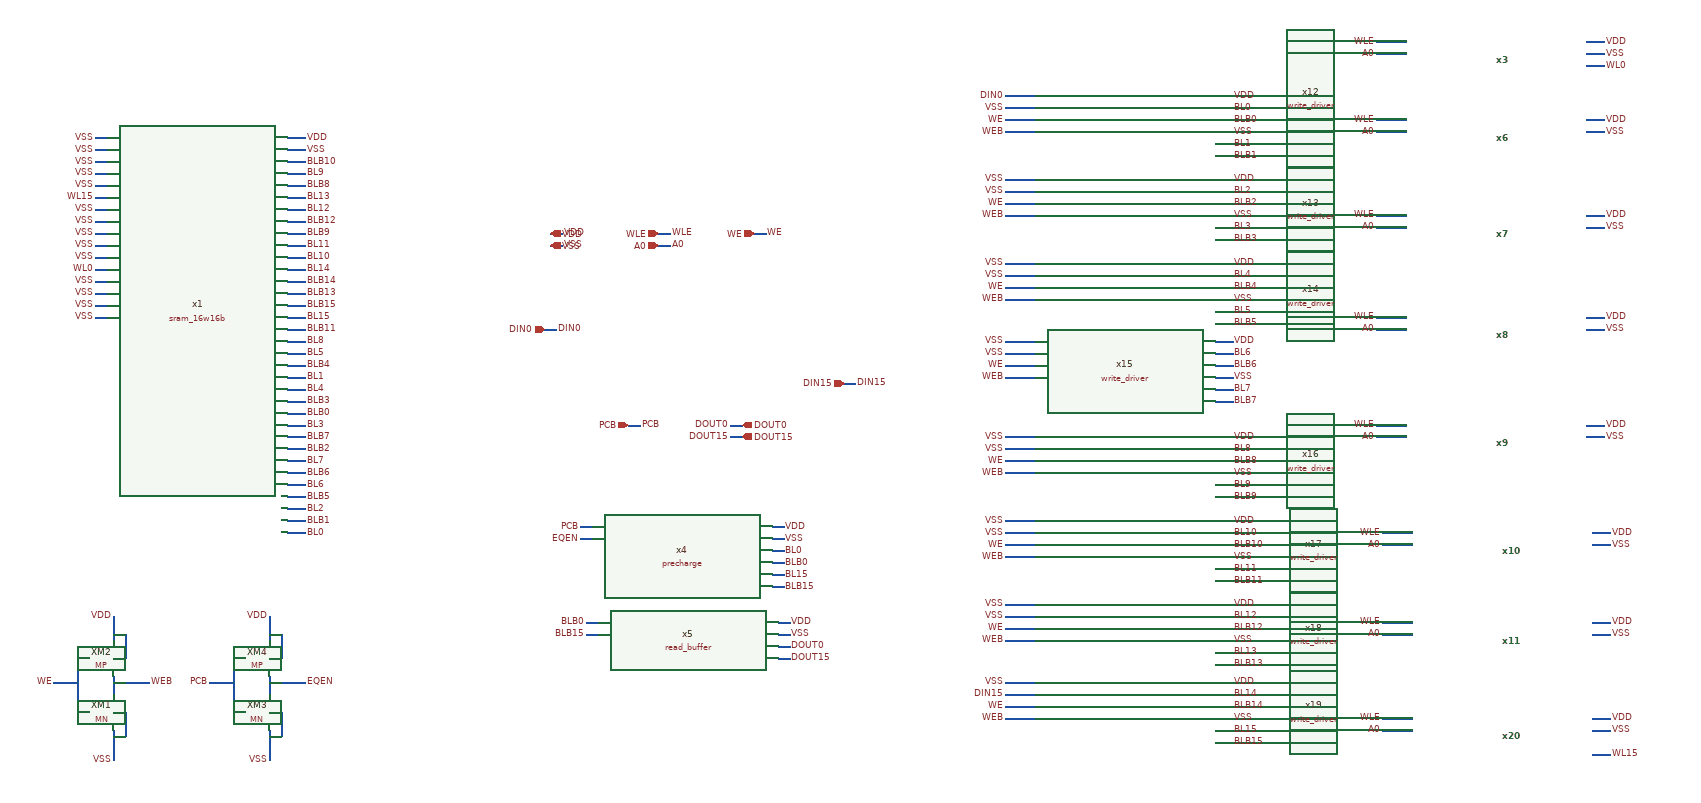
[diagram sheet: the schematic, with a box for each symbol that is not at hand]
v {xschem version=3.4.8RC file_version=1.3}
G {}
K {}
V {}
S {}
F {}
E {}
N 210 -880 230 -880 {lab=WL0}
N 210 -800 230 -800 {lab=VSS}
N 1020 -450 1040 -450 {lab=PCB}
N 1020 -430 1040 -430 {lab=EQEN}
N 1030 -290 1050 -290 {lab=BLB0}
N 1030 -270 1050 -270 {lab=BLB15}
N 1340 -450 1360 -450 {lab=VDD}
N 1340 -430 1360 -430 {lab=VSS}
N 1340 -410 1360 -410 {lab=BL0}
N 1340 -390 1360 -390 {lab=BLB0}
N 1340 -370 1360 -370 {lab=BL15}
N 1340 -350 1360 -350 {lab=BLB15}
N 1350 -290 1370 -290 {lab=VDD}
N 1350 -270 1370 -270 {lab=VSS}
N 1350 -250 1370 -250 {lab=DOUT0}
N 1350 -230 1370 -230 {lab=DOUT15}
N 970 -940 990 -940 {lab=VDD}
N 970 -920 990 -920 {lab=VSS}
N 1150 -940 1170 -940 {lab=WLE}
N 1150 -920 1170 -920 {lab=A0}
N 1310 -940 1330 -940 {lab=WE}
N 960 -780 980 -780 {lab=DIN0}
N 1100 -620 1120 -620 {lab=PCB}
N 1270 -620 1290 -620 {lab=DOUT0}
N 1270 -600 1290 -600 {lab=DOUT15}
N 240 -200 240 -170 {lab=WEB}
N 240 -110 240 -60 {lab=VSS}
N 240 -140 260 -140 {lab=VSS}
N 260 -140 260 -100 {lab=VSS}
N 240 -100 260 -100 {lab=VSS}
N 240 -300 240 -260 {lab=VDD}
N 180 -230 200 -230 {lab=WE}
N 180 -230 180 -140 {lab=WE}
N 180 -140 200 -140 {lab=WE}
N 240 -190 300 -190 {lab=WEB}
N 140 -190 180 -190 {lab=WE}
N 240 -230 260 -230 {lab=VDD}
N 260 -270 260 -230 {lab=VDD}
N 240 -270 260 -270 {lab=VDD}
N 500 -200 500 -170 {lab=EQEN}
N 500 -110 500 -60 {lab=VSS}
N 500 -140 520 -140 {lab=VSS}
N 520 -140 520 -100 {lab=VSS}
N 500 -100 520 -100 {lab=VSS}
N 500 -300 500 -260 {lab=VDD}
N 440 -230 460 -230 {lab=PCB}
N 440 -230 440 -140 {lab=PCB}
N 440 -140 460 -140 {lab=PCB}
N 500 -190 560 -190 {lab=EQEN}
N 400 -190 440 -190 {lab=PCB}
N 500 -230 520 -230 {lab=VDD}
N 520 -270 520 -230 {lab=VDD}
N 500 -270 520 -270 {lab=VDD}
N 530 -1080 560 -1080 {lab=VSS}
N 530 -1100 560 -1100 {lab=VDD}
N 530 -820 560 -820 {lab=BLB15}
N 530 -780 560 -780 {lab=BLB11}
N 530 -1020 560 -1020 {lab=BLB8}
N 530 -760 560 -760 {lab=BL8}
N 530 -960 560 -960 {lab=BLB12}
N 530 -1040 560 -1040 {lab=BL9}
N 530 -1060 560 -1060 {lab=BLB10}
N 530 -920 560 -920 {lab=BL11}
N 530 -900 560 -900 {lab=BL10}
N 530 -880 560 -880 {lab=BL14}
N 530 -840 560 -840 {lab=BLB13}
N 530 -980 560 -980 {lab=BL12}
N 530 -940 560 -940 {lab=BLB9}
N 530 -860 560 -860 {lab=BLB14}
N 530 -800 560 -800 {lab=BL15}
N 530 -1000 560 -1000 {lab=BL13}
N 530 -680 560 -680 {lab=BL4}
N 530 -640 560 -640 {lab=BLB0}
N 530 -620 560 -620 {lab=BL3}
N 530 -740 560 -740 {lab=BL5}
N 530 -700 560 -700 {lab=BL1}
N 530 -720 560 -720 {lab=BLB4}
N 530 -660 560 -660 {lab=BLB3}
N 530 -600 560 -600 {lab=BLB7}
N 530 -520 560 -520 {lab=BL6}
N 530 -480 560 -480 {lab=BL2}
N 530 -460 560 -460 {lab=BLB1}
N 530 -580 560 -580 {lab=BLB2}
N 530 -540 560 -540 {lab=BLB6}
N 530 -560 560 -560 {lab=BL7}
N 530 -500 560 -500 {lab=BLB5}
N 530 -440 560 -440 {lab=BL0}
N 2080 -1170 2110 -1170 {lab=VDD}
N 2080 -1110 2110 -1110 {lab=VSS}
N 1730 -1130 1780 -1130 {lab=WE}
N 1730 -1110 1780 -1110 {lab=WEB}
N 2080 -1150 2110 -1150 {lab=BL0}
N 2080 -1130 2110 -1130 {lab=BLB0}
N 2080 -1090 2110 -1090 {lab=BL1}
N 2080 -1070 2110 -1070 {lab=BLB1}
N 1730 -1170 1780 -1170 {lab=DIN0}
N 1730 -1150 1780 -1150 {lab=DIN1}
N 2080 -1030 2110 -1030 {lab=VDD}
N 2080 -970 2110 -970 {lab=VSS}
N 1730 -990 1780 -990 {lab=WE}
N 1730 -970 1780 -970 {lab=WEB}
N 2080 -1010 2110 -1010 {lab=BL2}
N 2080 -990 2110 -990 {lab=BLB2}
N 2080 -950 2110 -950 {lab=BL3}
N 2080 -930 2110 -930 {lab=BLB3}
N 1730 -1030 1780 -1030 {lab=DIN2}
N 1730 -1010 1780 -1010 {lab=DIN3}
N 2080 -890 2110 -890 {lab=VDD}
N 2080 -830 2110 -830 {lab=VSS}
N 1730 -850 1780 -850 {lab=WE}
N 1730 -830 1780 -830 {lab=WEB}
N 2080 -870 2110 -870 {lab=BL4}
N 2080 -850 2110 -850 {lab=BLB4}
N 2080 -810 2110 -810 {lab=BL5}
N 2080 -790 2110 -790 {lab=BLB5}
N 1730 -890 1780 -890 {lab=DIN4}
N 1730 -870 1780 -870 {lab=DIN5}
N 2080 -760 2110 -760 {lab=VDD}
N 2080 -700 2110 -700 {lab=VSS}
N 1730 -720 1780 -720 {lab=WE}
N 1730 -700 1780 -700 {lab=WEB}
N 2080 -740 2110 -740 {lab=BL6}
N 2080 -720 2110 -720 {lab=BLB6}
N 2080 -680 2110 -680 {lab=BL7}
N 2080 -660 2110 -660 {lab=BLB7}
N 1730 -760 1780 -760 {lab=DIN6}
N 1730 -740 1780 -740 {lab=DIN7}
N 2080 -600 2110 -600 {lab=VDD}
N 2080 -540 2110 -540 {lab=VSS}
N 1730 -560 1780 -560 {lab=WE}
N 1730 -540 1780 -540 {lab=WEB}
N 2080 -580 2110 -580 {lab=BL8}
N 2080 -560 2110 -560 {lab=BLB8}
N 2080 -520 2110 -520 {lab=BL9}
N 2080 -500 2110 -500 {lab=BLB9}
N 1730 -600 1780 -600 {lab=DIN8}
N 1730 -580 1780 -580 {lab=DIN9}
N 2080 -460 2110 -460 {lab=VDD}
N 2080 -400 2110 -400 {lab=VSS}
N 1730 -420 1780 -420 {lab=WE}
N 1730 -400 1780 -400 {lab=WEB}
N 2080 -440 2110 -440 {lab=BL10}
N 2080 -420 2110 -420 {lab=BLB10}
N 2080 -380 2110 -380 {lab=BL11}
N 2080 -360 2110 -360 {lab=BLB11}
N 1730 -460 1780 -460 {lab=DIN10}
N 1730 -440 1780 -440 {lab=DIN11}
N 2080 -320 2110 -320 {lab=VDD}
N 2080 -260 2110 -260 {lab=VSS}
N 1730 -280 1780 -280 {lab=WE}
N 1730 -260 1780 -260 {lab=WEB}
N 2080 -300 2110 -300 {lab=BL12}
N 2080 -280 2110 -280 {lab=BLB12}
N 2080 -240 2110 -240 {lab=BL13}
N 2080 -220 2110 -220 {lab=BLB13}
N 1730 -320 1780 -320 {lab=DIN12}
N 1730 -300 1780 -300 {lab=DIN13}
N 2080 -190 2110 -190 {lab=VDD}
N 2080 -130 2110 -130 {lab=VSS}
N 1730 -150 1780 -150 {lab=WE}
N 1730 -130 1780 -130 {lab=WEB}
N 2080 -170 2110 -170 {lab=BL14}
N 2080 -150 2110 -150 {lab=BLB14}
N 2080 -110 2110 -110 {lab=BL15}
N 2080 -90 2110 -90 {lab=BLB15}
N 1730 -190 1780 -190 {lab=DIN14}
N 1730 -170 1780 -170 {lab=DIN15}
N 1460 -690 1480 -690 {lab=DIN15}
N 2350 -1260 2400 -1260 {lab=WLE}
N 2350 -1240 2400 -1240 {lab=A0}
N 2700 -1260 2730 -1260 {lab=VDD}
N 2700 -1240 2730 -1240 {lab=VSS}
N 2700 -1220 2730 -1220 {lab=WL0}
N 2350 -1130 2400 -1130 {lab=WLE}
N 2350 -1110 2400 -1110 {lab=A0}
N 2700 -1130 2730 -1130 {lab=VDD}
N 2350 -970 2400 -970 {lab=WLE}
N 2350 -950 2400 -950 {lab=A0}
N 2700 -970 2730 -970 {lab=VDD}
N 2700 -950 2730 -950 {lab=VSS}
N 2350 -800 2400 -800 {lab=WLE}
N 2350 -780 2400 -780 {lab=A0}
N 2700 -800 2730 -800 {lab=VDD}
N 2700 -780 2730 -780 {lab=VSS}
N 2350 -620 2400 -620 {lab=WLE}
N 2350 -600 2400 -600 {lab=A0}
N 2700 -620 2730 -620 {lab=VDD}
N 2700 -600 2730 -600 {lab=VSS}
N 2360 -440 2410 -440 {lab=WLE}
N 2360 -420 2410 -420 {lab=A0}
N 2710 -440 2740 -440 {lab=VDD}
N 2710 -420 2740 -420 {lab=VSS}
N 2360 -290 2410 -290 {lab=WLE}
N 2360 -270 2410 -270 {lab=A0}
N 2710 -290 2740 -290 {lab=VDD}
N 2710 -270 2740 -270 {lab=VSS}
N 2360 -130 2410 -130 {lab=WLE}
N 2360 -110 2410 -110 {lab=A0}
N 2710 -130 2740 -130 {lab=VDD}
N 2710 -110 2740 -110 {lab=VSS}
N 2710 -70 2740 -70 {lab=WL15}
N 2700 -1110 2730 -1110 {lab=VSS}
N 210 -1000 230 -1000 {lab=WL15}
N 210 -820 230 -820 {lab=VSS}
N 210 -840 230 -840 {lab=VSS}
N 210 -860 230 -860 {lab=VSS}
N 210 -900 230 -900 {lab=VSS}
N 210 -920 230 -920 {lab=VSS}
N 210 -940 230 -940 {lab=VSS}
N 210 -960 230 -960 {lab=VSS}
N 210 -980 230 -980 {lab=VSS}
N 210 -1020 230 -1020 {lab=VSS}
N 210 -1040 230 -1040 {lab=VSS}
N 210 -1060 230 -1060 {lab=VSS}
N 210 -1080 230 -1080 {lab=VSS}
N 210 -1100 230 -1100 {lab=VSS}
C {precharge.sym} 1190 -400 0 0 {name=x4}
C {read_buffer.sym} 1200 -260 0 0 {name=x5}
C {devices/iopin.sym} 970 -940 0 1 {name=p1 lab=VDD}
C {devices/ipin.sym} 1150 -940 0 0 {name=p2 lab=WLE}
C {devices/opin.sym} 1290 -620 0 0 {name=p3 lab=DOUT0}
C {devices/lab_pin.sym} 210 -880 0 0 {name=p10 sig_type=std_logic lab=WL0}
C {devices/lab_pin.sym} 210 -800 0 0 {name=p11 sig_type=std_logic lab=VSS}
C {devices/lab_pin.sym} 1020 -450 0 0 {name=p17 sig_type=std_logic lab=PCB}
C {devices/lab_pin.sym} 1020 -430 0 0 {name=p18 sig_type=std_logic lab=EQEN}
C {devices/lab_pin.sym} 1030 -290 0 0 {name=p30 sig_type=std_logic lab=BLB0}
C {devices/lab_pin.sym} 1030 -270 0 0 {name=p31 sig_type=std_logic lab=BLB15}
C {devices/lab_pin.sym} 1360 -450 0 1 {name=p32 sig_type=std_logic lab=VDD}
C {devices/lab_pin.sym} 1360 -430 0 1 {name=p33 sig_type=std_logic lab=VSS}
C {devices/lab_pin.sym} 1360 -410 0 1 {name=p34 sig_type=std_logic lab=BL0}
C {devices/lab_pin.sym} 1360 -390 0 1 {name=p35 sig_type=std_logic lab=BLB0}
C {devices/lab_pin.sym} 1360 -370 0 1 {name=p36 sig_type=std_logic lab=BL15}
C {devices/lab_pin.sym} 1360 -350 0 1 {name=p37 sig_type=std_logic lab=BLB15}
C {devices/lab_pin.sym} 1370 -290 0 1 {name=p38 sig_type=std_logic lab=VDD}
C {devices/lab_pin.sym} 1370 -270 0 1 {name=p39 sig_type=std_logic lab=VSS}
C {devices/lab_pin.sym} 1370 -250 0 1 {name=p40 sig_type=std_logic lab=DOUT0}
C {devices/lab_pin.sym} 1370 -230 0 1 {name=p41 sig_type=std_logic lab=DOUT15}
C {devices/lab_pin.sym} 990 -940 0 1 {name=p42 sig_type=std_logic lab=VDD}
C {devices/iopin.sym} 970 -920 0 1 {name=p43 lab=VSS}
C {devices/lab_pin.sym} 990 -920 0 1 {name=p44 sig_type=std_logic lab=VSS}
C {devices/lab_pin.sym} 1170 -940 0 1 {name=p45 sig_type=std_logic lab=WLE}
C {devices/ipin.sym} 1150 -920 0 0 {name=p46 lab=A0}
C {devices/lab_pin.sym} 1170 -920 0 1 {name=p47 sig_type=std_logic lab=A0}
C {devices/ipin.sym} 1310 -940 0 0 {name=p48 lab=WE}
C {devices/lab_pin.sym} 1330 -940 0 1 {name=p49 sig_type=std_logic lab=WE}
C {devices/ipin.sym} 960 -780 0 0 {name=p52 lab=DIN0}
C {devices/lab_pin.sym} 980 -780 0 1 {name=p53 sig_type=std_logic lab=DIN0}
C {devices/ipin.sym} 1100 -620 0 0 {name=p56 lab=PCB}
C {devices/lab_pin.sym} 1120 -620 0 1 {name=p57 sig_type=std_logic lab=PCB}
C {devices/lab_pin.sym} 1270 -620 0 0 {name=p60 sig_type=std_logic lab=DOUT0}
C {devices/opin.sym} 1290 -600 0 0 {name=p61 lab=DOUT15}
C {devices/lab_pin.sym} 1270 -600 0 0 {name=p62 sig_type=std_logic lab=DOUT15}
C {devices/lab_pin.sym} 240 -300 0 0 {name=p63 sig_type=std_logic lab=VDD}
C {devices/lab_pin.sym} 140 -190 0 0 {name=p64 sig_type=std_logic lab=WE}
C {devices/lab_pin.sym} 300 -190 0 1 {name=p65 sig_type=std_logic lab=WEB}
C {devices/lab_pin.sym} 240 -60 0 0 {name=p66 sig_type=std_logic lab=VSS}
C {TR-1umLIB/MN.sym} 200 -140 0 0 {name=XM1
model=NMOS
w=3.4u
l=1u
m=1
spiceprefix=X
as=0
ad=0
ps=0
pd=0
nrd=0
nrs=0}
C {TR-1umLIB/MP.sym} 200 -230 0 0 {name=XM2
model=PMOS
w=6.8u
l=1u
m=1
spiceprefix=X
as=0
ad=0
ps=0
pd=0
nrd=0
nrs=0}
C {devices/lab_pin.sym} 500 -300 0 0 {name=p50 sig_type=std_logic lab=VDD}
C {devices/lab_pin.sym} 400 -190 0 0 {name=p51 sig_type=std_logic lab=PCB}
C {devices/lab_pin.sym} 500 -60 0 0 {name=p68 sig_type=std_logic lab=VSS}
C {TR-1umLIB/MN.sym} 460 -140 0 0 {name=XM3
model=NMOS
w=3.4u
l=1u
m=1
spiceprefix=X
as=0
ad=0
ps=0
pd=0
nrd=0
nrs=0}
C {TR-1umLIB/MP.sym} 460 -230 0 0 {name=XM4
model=PMOS
w=6.8u
l=1u
m=1
spiceprefix=X
as=0
ad=0
ps=0
pd=0
nrd=0
nrs=0}
C {devices/lab_pin.sym} 560 -1100 0 1 {name=p127 sig_type=std_logic lab=VDD}
C {devices/lab_pin.sym} 560 -820 0 1 {name=p128 sig_type=std_logic lab=BLB15}
C {devices/lab_pin.sym} 560 -780 0 1 {name=p129 sig_type=std_logic lab=BLB11}
C {devices/lab_pin.sym} 560 -1020 0 1 {name=p130 sig_type=std_logic lab=BLB8}
C {devices/lab_pin.sym} 560 -1080 0 1 {name=p131 sig_type=std_logic lab=VSS}
C {devices/lab_pin.sym} 560 -760 0 1 {name=p132 sig_type=std_logic lab=BL8}
C {devices/lab_pin.sym} 560 -960 0 1 {name=p133 sig_type=std_logic lab=BLB12}
C {devices/lab_pin.sym} 560 -1040 0 1 {name=p134 sig_type=std_logic lab=BL9}
C {devices/lab_pin.sym} 560 -1060 0 1 {name=p135 sig_type=std_logic lab=BLB10}
C {devices/lab_pin.sym} 560 -920 0 1 {name=p136 sig_type=std_logic lab=BL11}
C {devices/lab_pin.sym} 560 -900 0 1 {name=p137 sig_type=std_logic lab=BL10}
C {devices/lab_pin.sym} 560 -880 0 1 {name=p138 sig_type=std_logic lab=BL14}
C {devices/lab_pin.sym} 560 -840 0 1 {name=p139 sig_type=std_logic lab=BLB13}
C {devices/lab_pin.sym} 560 -980 0 1 {name=p140 sig_type=std_logic lab=BL12}
C {devices/lab_pin.sym} 560 -940 0 1 {name=p141 sig_type=std_logic lab=BLB9}
C {devices/lab_pin.sym} 560 -860 0 1 {name=p142 sig_type=std_logic lab=BLB14}
C {devices/lab_pin.sym} 560 -800 0 1 {name=p143 sig_type=std_logic lab=BL15}
C {devices/lab_pin.sym} 560 -1000 0 1 {name=p144 sig_type=std_logic lab=BL13}
C {devices/lab_pin.sym} 560 -680 0 1 {name=p145 sig_type=std_logic lab=BL4}
C {devices/lab_pin.sym} 560 -640 0 1 {name=p146 sig_type=std_logic lab=BLB0}
C {devices/lab_pin.sym} 560 -620 0 1 {name=p147 sig_type=std_logic lab=BL3}
C {devices/lab_pin.sym} 560 -740 0 1 {name=p148 sig_type=std_logic lab=BL5}
C {devices/lab_pin.sym} 560 -700 0 1 {name=p149 sig_type=std_logic lab=BL1}
C {devices/lab_pin.sym} 560 -720 0 1 {name=p150 sig_type=std_logic lab=BLB4}
C {devices/lab_pin.sym} 560 -660 0 1 {name=p151 sig_type=std_logic lab=BLB3}
C {devices/lab_pin.sym} 560 -600 0 1 {name=p152 sig_type=std_logic lab=BLB7}
C {devices/lab_pin.sym} 560 -520 0 1 {name=p153 sig_type=std_logic lab=BL6}
C {devices/lab_pin.sym} 560 -480 0 1 {name=p154 sig_type=std_logic lab=BL2}
C {devices/lab_pin.sym} 560 -460 0 1 {name=p155 sig_type=std_logic lab=BLB1}
C {devices/lab_pin.sym} 560 -580 0 1 {name=p156 sig_type=std_logic lab=BLB2}
C {devices/lab_pin.sym} 560 -540 0 1 {name=p157 sig_type=std_logic lab=BLB6}
C {devices/lab_pin.sym} 560 -560 0 1 {name=p158 sig_type=std_logic lab=BL7}
C {devices/lab_pin.sym} 560 -500 0 1 {name=p159 sig_type=std_logic lab=BLB5}
C {devices/lab_pin.sym} 560 -440 0 1 {name=p160 sig_type=std_logic lab=BL0}
C {write_driver.sym} 1930 -1120 0 0 {name=x12}
C {devices/lab_pin.sym} 2110 -1170 0 1 {name=p12 sig_type=std_logic lab=VDD}
C {devices/lab_pin.sym} 2110 -1110 0 1 {name=p13 sig_type=std_logic lab=VSS}
C {devices/lab_pin.sym} 1730 -1130 0 0 {name=p14 sig_type=std_logic lab=WE}
C {devices/lab_pin.sym} 1730 -1110 0 0 {name=p15 sig_type=std_logic lab=WEB}
C {devices/lab_pin.sym} 2110 -1150 0 1 {name=p16 sig_type=std_logic lab=BL0}
C {devices/lab_pin.sym} 2110 -1130 0 1 {name=p23 sig_type=std_logic lab=BLB0}
C {devices/lab_pin.sym} 2110 -1090 0 1 {name=p58 sig_type=std_logic lab=BL1}
C {devices/lab_pin.sym} 2110 -1070 0 1 {name=p59 sig_type=std_logic lab=BLB1}
C {devices/lab_pin.sym} 1730 -1170 0 0 {name=p69 sig_type=std_logic lab=DIN0}
C {devices/lab_pin.sym} 1730 -1150 0 0 {name=p70 sig_type=std_logic lab=VSS}
C {write_driver.sym} 1930 -980 0 0 {name=x13}
C {devices/lab_pin.sym} 2110 -1030 0 1 {name=p71 sig_type=std_logic lab=VDD}
C {devices/lab_pin.sym} 2110 -970 0 1 {name=p72 sig_type=std_logic lab=VSS}
C {devices/lab_pin.sym} 1730 -990 0 0 {name=p73 sig_type=std_logic lab=WE}
C {devices/lab_pin.sym} 1730 -970 0 0 {name=p74 sig_type=std_logic lab=WEB}
C {devices/lab_pin.sym} 2110 -1010 0 1 {name=p75 sig_type=std_logic lab=BL2}
C {devices/lab_pin.sym} 2110 -990 0 1 {name=p76 sig_type=std_logic lab=BLB2}
C {devices/lab_pin.sym} 2110 -950 0 1 {name=p77 sig_type=std_logic lab=BL3}
C {devices/lab_pin.sym} 2110 -930 0 1 {name=p78 sig_type=std_logic lab=BLB3}
C {devices/lab_pin.sym} 1730 -1030 0 0 {name=p161 sig_type=std_logic lab=VSS}
C {devices/lab_pin.sym} 1730 -1010 0 0 {name=p162 sig_type=std_logic lab=VSS}
C {write_driver.sym} 1930 -840 0 0 {name=x14}
C {devices/lab_pin.sym} 2110 -890 0 1 {name=p163 sig_type=std_logic lab=VDD}
C {devices/lab_pin.sym} 2110 -830 0 1 {name=p164 sig_type=std_logic lab=VSS}
C {devices/lab_pin.sym} 1730 -850 0 0 {name=p165 sig_type=std_logic lab=WE}
C {devices/lab_pin.sym} 1730 -830 0 0 {name=p166 sig_type=std_logic lab=WEB}
C {devices/lab_pin.sym} 2110 -870 0 1 {name=p167 sig_type=std_logic lab=BL4}
C {devices/lab_pin.sym} 2110 -850 0 1 {name=p168 sig_type=std_logic lab=BLB4}
C {devices/lab_pin.sym} 2110 -810 0 1 {name=p169 sig_type=std_logic lab=BL5}
C {devices/lab_pin.sym} 2110 -790 0 1 {name=p170 sig_type=std_logic lab=BLB5}
C {devices/lab_pin.sym} 1730 -890 0 0 {name=p171 sig_type=std_logic lab=VSS}
C {devices/lab_pin.sym} 1730 -870 0 0 {name=p172 sig_type=std_logic lab=VSS}
C {write_driver.sym} 1930 -710 0 0 {name=x15}
C {devices/lab_pin.sym} 2110 -760 0 1 {name=p173 sig_type=std_logic lab=VDD}
C {devices/lab_pin.sym} 2110 -700 0 1 {name=p174 sig_type=std_logic lab=VSS}
C {devices/lab_pin.sym} 1730 -720 0 0 {name=p175 sig_type=std_logic lab=WE}
C {devices/lab_pin.sym} 1730 -700 0 0 {name=p176 sig_type=std_logic lab=WEB}
C {devices/lab_pin.sym} 2110 -740 0 1 {name=p177 sig_type=std_logic lab=BL6}
C {devices/lab_pin.sym} 2110 -720 0 1 {name=p178 sig_type=std_logic lab=BLB6}
C {devices/lab_pin.sym} 2110 -680 0 1 {name=p179 sig_type=std_logic lab=BL7}
C {devices/lab_pin.sym} 2110 -660 0 1 {name=p180 sig_type=std_logic lab=BLB7}
C {devices/lab_pin.sym} 1730 -760 0 0 {name=p181 sig_type=std_logic lab=VSS}
C {devices/lab_pin.sym} 1730 -740 0 0 {name=p182 sig_type=std_logic lab=VSS}
C {write_driver.sym} 1930 -550 0 0 {name=x16}
C {devices/lab_pin.sym} 2110 -600 0 1 {name=p183 sig_type=std_logic lab=VDD}
C {devices/lab_pin.sym} 2110 -540 0 1 {name=p184 sig_type=std_logic lab=VSS}
C {devices/lab_pin.sym} 1730 -560 0 0 {name=p185 sig_type=std_logic lab=WE}
C {devices/lab_pin.sym} 1730 -540 0 0 {name=p186 sig_type=std_logic lab=WEB}
C {devices/lab_pin.sym} 2110 -580 0 1 {name=p187 sig_type=std_logic lab=BL8}
C {devices/lab_pin.sym} 2110 -560 0 1 {name=p188 sig_type=std_logic lab=BLB8}
C {devices/lab_pin.sym} 2110 -520 0 1 {name=p189 sig_type=std_logic lab=BL9}
C {devices/lab_pin.sym} 2110 -500 0 1 {name=p190 sig_type=std_logic lab=BLB9}
C {devices/lab_pin.sym} 1730 -600 0 0 {name=p191 sig_type=std_logic lab=VSS}
C {devices/lab_pin.sym} 1730 -580 0 0 {name=p192 sig_type=std_logic lab=VSS}
C {write_driver.sym} 1930 -410 0 0 {name=x17}
C {devices/lab_pin.sym} 2110 -460 0 1 {name=p193 sig_type=std_logic lab=VDD}
C {devices/lab_pin.sym} 2110 -400 0 1 {name=p194 sig_type=std_logic lab=VSS}
C {devices/lab_pin.sym} 1730 -420 0 0 {name=p195 sig_type=std_logic lab=WE}
C {devices/lab_pin.sym} 1730 -400 0 0 {name=p196 sig_type=std_logic lab=WEB}
C {devices/lab_pin.sym} 2110 -440 0 1 {name=p197 sig_type=std_logic lab=BL10}
C {devices/lab_pin.sym} 2110 -420 0 1 {name=p198 sig_type=std_logic lab=BLB10}
C {devices/lab_pin.sym} 2110 -380 0 1 {name=p199 sig_type=std_logic lab=BL11}
C {devices/lab_pin.sym} 2110 -360 0 1 {name=p200 sig_type=std_logic lab=BLB11}
C {devices/lab_pin.sym} 1730 -460 0 0 {name=p201 sig_type=std_logic lab=VSS}
C {devices/lab_pin.sym} 1730 -440 0 0 {name=p202 sig_type=std_logic lab=VSS}
C {write_driver.sym} 1930 -270 0 0 {name=x18}
C {devices/lab_pin.sym} 2110 -320 0 1 {name=p203 sig_type=std_logic lab=VDD}
C {devices/lab_pin.sym} 2110 -260 0 1 {name=p204 sig_type=std_logic lab=VSS}
C {devices/lab_pin.sym} 1730 -280 0 0 {name=p205 sig_type=std_logic lab=WE}
C {devices/lab_pin.sym} 1730 -260 0 0 {name=p206 sig_type=std_logic lab=WEB}
C {devices/lab_pin.sym} 2110 -300 0 1 {name=p207 sig_type=std_logic lab=BL12}
C {devices/lab_pin.sym} 2110 -280 0 1 {name=p208 sig_type=std_logic lab=BLB12}
C {devices/lab_pin.sym} 2110 -240 0 1 {name=p209 sig_type=std_logic lab=BL13}
C {devices/lab_pin.sym} 2110 -220 0 1 {name=p210 sig_type=std_logic lab=BLB13}
C {devices/lab_pin.sym} 1730 -320 0 0 {name=p211 sig_type=std_logic lab=VSS}
C {devices/lab_pin.sym} 1730 -300 0 0 {name=p212 sig_type=std_logic lab=VSS}
C {write_driver.sym} 1930 -140 0 0 {name=x19}
C {devices/lab_pin.sym} 2110 -190 0 1 {name=p213 sig_type=std_logic lab=VDD}
C {devices/lab_pin.sym} 2110 -130 0 1 {name=p214 sig_type=std_logic lab=VSS}
C {devices/lab_pin.sym} 1730 -150 0 0 {name=p215 sig_type=std_logic lab=WE}
C {devices/lab_pin.sym} 1730 -130 0 0 {name=p216 sig_type=std_logic lab=WEB}
C {devices/lab_pin.sym} 2110 -170 0 1 {name=p217 sig_type=std_logic lab=BL14}
C {devices/lab_pin.sym} 2110 -150 0 1 {name=p218 sig_type=std_logic lab=BLB14}
C {devices/lab_pin.sym} 2110 -110 0 1 {name=p219 sig_type=std_logic lab=BL15}
C {devices/lab_pin.sym} 2110 -90 0 1 {name=p220 sig_type=std_logic lab=BLB15}
C {devices/lab_pin.sym} 1730 -190 0 0 {name=p221 sig_type=std_logic lab=VSS}
C {devices/lab_pin.sym} 1730 -170 0 0 {name=p222 sig_type=std_logic lab=DIN15}
C {devices/ipin.sym} 1460 -690 0 0 {name=p95 lab=DIN15}
C {devices/lab_pin.sym} 1480 -690 0 1 {name=p96 sig_type=std_logic lab=DIN15}
C {sram_16w16b.sym} 380 -770 0 0 {name=x1}
C {decoder.sym} 2550 -1230 0 0 {name=x3}
C {devices/lab_pin.sym} 2350 -1260 0 0 {name=p97 sig_type=std_logic lab=WLE}
C {devices/lab_pin.sym} 2350 -1240 0 0 {name=p98 sig_type=std_logic lab=A0}
C {devices/lab_pin.sym} 2730 -1260 0 1 {name=p99 sig_type=std_logic lab=VDD}
C {devices/lab_pin.sym} 2730 -1240 0 1 {name=p100 sig_type=std_logic lab=VSS}
C {devices/lab_pin.sym} 2730 -1220 0 1 {name=p101 sig_type=std_logic lab=WL0}
C {decoder.sym} 2550 -1100 0 0 {name=x6}
C {devices/lab_pin.sym} 2350 -1130 0 0 {name=p102 sig_type=std_logic lab=WLE}
C {devices/lab_pin.sym} 2350 -1110 0 0 {name=p103 sig_type=std_logic lab=A0}
C {devices/lab_pin.sym} 2730 -1130 0 1 {name=p104 sig_type=std_logic lab=VDD}
C {devices/lab_pin.sym} 2730 -1110 0 1 {name=p105 sig_type=std_logic lab=VSS}
C {decoder.sym} 2550 -940 0 0 {name=x7}
C {devices/lab_pin.sym} 2350 -970 0 0 {name=p106 sig_type=std_logic lab=WLE}
C {devices/lab_pin.sym} 2350 -950 0 0 {name=p107 sig_type=std_logic lab=A0}
C {devices/lab_pin.sym} 2730 -970 0 1 {name=p108 sig_type=std_logic lab=VDD}
C {devices/lab_pin.sym} 2730 -950 0 1 {name=p109 sig_type=std_logic lab=VSS}
C {decoder.sym} 2550 -770 0 0 {name=x8}
C {devices/lab_pin.sym} 2350 -800 0 0 {name=p110 sig_type=std_logic lab=WLE}
C {devices/lab_pin.sym} 2350 -780 0 0 {name=p111 sig_type=std_logic lab=A0}
C {devices/lab_pin.sym} 2730 -800 0 1 {name=p112 sig_type=std_logic lab=VDD}
C {devices/lab_pin.sym} 2730 -780 0 1 {name=p113 sig_type=std_logic lab=VSS}
C {decoder.sym} 2550 -590 0 0 {name=x9}
C {devices/lab_pin.sym} 2350 -620 0 0 {name=p114 sig_type=std_logic lab=WLE}
C {devices/lab_pin.sym} 2350 -600 0 0 {name=p115 sig_type=std_logic lab=A0}
C {devices/lab_pin.sym} 2730 -620 0 1 {name=p116 sig_type=std_logic lab=VDD}
C {devices/lab_pin.sym} 2730 -600 0 1 {name=p117 sig_type=std_logic lab=VSS}
C {decoder.sym} 2560 -410 0 0 {name=x10}
C {devices/lab_pin.sym} 2360 -440 0 0 {name=p118 sig_type=std_logic lab=WLE}
C {devices/lab_pin.sym} 2360 -420 0 0 {name=p119 sig_type=std_logic lab=A0}
C {devices/lab_pin.sym} 2740 -440 0 1 {name=p120 sig_type=std_logic lab=VDD}
C {devices/lab_pin.sym} 2740 -420 0 1 {name=p121 sig_type=std_logic lab=VSS}
C {decoder.sym} 2560 -260 0 0 {name=x11}
C {devices/lab_pin.sym} 2360 -290 0 0 {name=p122 sig_type=std_logic lab=WLE}
C {devices/lab_pin.sym} 2360 -270 0 0 {name=p123 sig_type=std_logic lab=A0}
C {devices/lab_pin.sym} 2740 -290 0 1 {name=p124 sig_type=std_logic lab=VDD}
C {devices/lab_pin.sym} 2740 -270 0 1 {name=p125 sig_type=std_logic lab=VSS}
C {decoder.sym} 2560 -100 0 0 {name=x20}
C {devices/lab_pin.sym} 2360 -130 0 0 {name=p126 sig_type=std_logic lab=WLE}
C {devices/lab_pin.sym} 2360 -110 0 0 {name=p223 sig_type=std_logic lab=A0}
C {devices/lab_pin.sym} 2740 -130 0 1 {name=p224 sig_type=std_logic lab=VDD}
C {devices/lab_pin.sym} 2740 -110 0 1 {name=p225 sig_type=std_logic lab=VSS}
C {devices/lab_pin.sym} 2740 -70 0 1 {name=p226 sig_type=std_logic lab=WL15}
C {devices/lab_pin.sym} 210 -1000 0 0 {name=p229 sig_type=std_logic lab=WL15}
C {devices/lab_pin.sym} 210 -820 0 0 {name=p4 sig_type=std_logic lab=VSS}
C {devices/lab_pin.sym} 210 -840 0 0 {name=p5 sig_type=std_logic lab=VSS}
C {devices/lab_pin.sym} 210 -860 0 0 {name=p6 sig_type=std_logic lab=VSS}
C {devices/lab_pin.sym} 210 -900 0 0 {name=p7 sig_type=std_logic lab=VSS}
C {devices/lab_pin.sym} 210 -920 0 0 {name=p8 sig_type=std_logic lab=VSS}
C {devices/lab_pin.sym} 210 -940 0 0 {name=p9 sig_type=std_logic lab=VSS}
C {devices/lab_pin.sym} 210 -960 0 0 {name=p67 sig_type=std_logic lab=VSS}
C {devices/lab_pin.sym} 210 -980 0 0 {name=p227 sig_type=std_logic lab=VSS}
C {devices/lab_pin.sym} 210 -1020 0 0 {name=p228 sig_type=std_logic lab=VSS}
C {devices/lab_pin.sym} 210 -1040 0 0 {name=p230 sig_type=std_logic lab=VSS}
C {devices/lab_pin.sym} 210 -1060 0 0 {name=p231 sig_type=std_logic lab=VSS}
C {devices/lab_pin.sym} 210 -1080 0 0 {name=p232 sig_type=std_logic lab=VSS}
C {devices/lab_pin.sym} 210 -1100 0 0 {name=p233 sig_type=std_logic lab=VSS}
C {devices/lab_pin.sym} 560 -190 0 1 {name=p234 sig_type=std_logic lab=EQEN}
